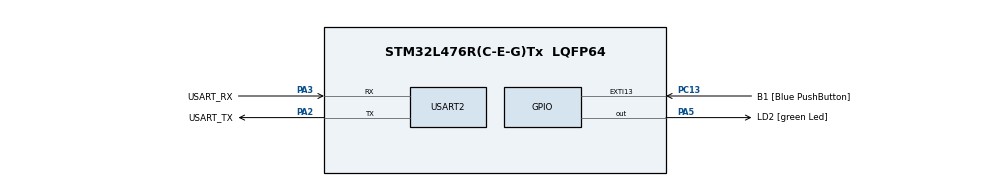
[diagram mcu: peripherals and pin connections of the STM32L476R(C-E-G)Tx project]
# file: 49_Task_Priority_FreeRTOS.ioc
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FREERTOS.Tasks01=defaultTask,0,128,StartDefaultTask,Default,NULL,Dynamic,NULL,NULL
Mcu.Family=STM32L4
Mcu.Name=STM32L476R(C-E-G)Tx
Mcu.Package=LQFP64
NVIC.PriorityGroup=NVIC_PRIORITYGROUP_4
PA13\ (JTMS-SWDIO).GPIO_Label=TMS
PA13\ (JTMS-SWDIO).Mode=Serial_Wire
PA13\ (JTMS-SWDIO).Signal=SYS_JTMS-SWDIO
PA14\ (JTCK-SWCLK).GPIO_Label=TCK
PA14\ (JTCK-SWCLK).Mode=Serial_Wire
PA14\ (JTCK-SWCLK).Signal=SYS_JTCK-SWCLK
PA2.GPIO_Label=USART_TX
PA2.GPIO_Mode=GPIO_MODE_AF_PP
PA2.GPIO_PuPd=GPIO_NOPULL
PA2.GPIO_Speed=GPIO_SPEED_FREQ_VERY_HIGH
PA2.Mode=Asynchronous
PA2.Signal=USART2_TX
PA3.GPIO_Label=USART_RX
PA3.GPIO_Mode=GPIO_MODE_AF_PP
PA3.GPIO_PuPd=GPIO_NOPULL
PA3.GPIO_Speed=GPIO_SPEED_FREQ_VERY_HIGH
PA3.Mode=Asynchronous
PA3.Signal=USART2_RX
PA5.GPIO_Label=LD2 [green Led]
PA5.GPIO_ModeDefaultOutputPP=GPIO_MODE_OUTPUT_PP
PA5.GPIO_PuPd=GPIO_NOPULL
PA5.GPIO_Speed=GPIO_SPEED_FREQ_LOW
PA5.Signal=GPIO_Output
PB3\ (JTDO-TRACESWO).GPIO_Label=SWO
PB3\ (JTDO-TRACESWO).Signal=SYS_JTDO-SWO
PC13.GPIO_Label=B1 [Blue PushButton]
PC13.GPIO_ModeDefaultEXTI=GPIO_MODE_IT_FALLING
PC13.GPIO_PuPd=GPIO_NOPULL
PC13.Signal=GPXTI13
PC14-OSC32_IN\ (PC14).Mode=LSE-External-Oscillator
PC14-OSC32_IN\ (PC14).Signal=RCC_OSC32_IN
PC15-OSC32_OUT\ (PC15).Mode=LSE-External-Oscillator
PC15-OSC32_OUT\ (PC15).Signal=RCC_OSC32_OUT
PH0-OSC_IN\ (PH0).Signal=RCC_OSC_IN
PH1-OSC_OUT\ (PH1).Signal=RCC_OSC_OUT
ProjectManager.HeapSize=0x200
ProjectManager.StackSize=0x400
ProjectManager.TargetToolchain=STM32CubeIDE
RCC.ADCFreq_Value=64000000
RCC.AHBFreq_Value=80000000
RCC.APB1Freq_Value=80000000
RCC.APB1TimFreq_Value=80000000
RCC.APB2Freq_Value=80000000
RCC.APB2TimFreq_Value=80000000
RCC.CortexFreq_Value=80000000
RCC.HCLKFreq_Value=80000000
RCC.HSE_VALUE=8000000
RCC.HSI_VALUE=16000000
RCC.MSI_VALUE=4000000
RCC.PLLN=10
RCC.PLLSourceVirtual=RCC_PLLSOURCE_HSI
RCC.PREFETCH_ENABLE=1
RCC.SYSCLKFreq_VALUE=80000000
RCC.SYSCLKSource=RCC_SYSCLKSOURCE_PLLCLK
RCC.USBFreq_Value=64000000
RCC.VCOOutputFreq_Value=160000000
USART2.VirtualMode-Asynchronous=VM_ASYNC
VP_FREERTOS_VS_CMSIS_V1.Mode=CMSIS_V1
board=NUCLEO-L476RG

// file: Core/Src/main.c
#include "main.h"
#include "FreeRTOS.h"
#include "task.h"
#include <stdio.h>

/* UART Handle */
UART_HandleTypeDef huart2;

/* Function Prototypes */
void SystemClock_Config(void);
static void MX_GPIO_Init(void);
static void MX_USART2_UART_Init(void);

/* Task Functions */
void HighPriorityTask(void *params);
void MediumPriorityTask(void *params);
void LowPriorityTask(void *params);

/* Redirect printf to UART */
int _write(int file, char *ptr, int len)
{
    HAL_UART_Transmit(&huart2,(uint8_t*)ptr,len,HAL_MAX_DELAY);
    return len;
}

int main(void)
{
    HAL_Init();
    SystemClock_Config();
    MX_GPIO_Init();
    MX_USART2_UART_Init();

    /* Create Tasks */

    xTaskCreate(HighPriorityTask,
                "High Priority",
                200,
                NULL,
                3,
                NULL);

    xTaskCreate(MediumPriorityTask,
                "Medium Priority",
                200,
                NULL,
                2,
                NULL);

    xTaskCreate(LowPriorityTask,
                "Low Priority",
                200,
                NULL,
                1,
                NULL);

    vTaskStartScheduler();

    while(1);
}

/* High Priority Task */
void HighPriorityTask(void *params)
{
    while(1)
    {
        HAL_GPIO_TogglePin(GPIOA, GPIO_PIN_5);
        printf("High Priority Task Running\r\n");
        vTaskDelay(pdMS_TO_TICKS(500));
    }
}

/* Medium Priority Task */
void MediumPriorityTask(void *params)
{
    while(1)
    {
        printf("Medium Priority Task Running\r\n");
        vTaskDelay(pdMS_TO_TICKS(1000));
    }
}

/* Low Priority Task */
void LowPriorityTask(void *params)
{
    while(1)
    {
        printf("Low Priority Task Running\r\n");
        vTaskDelay(pdMS_TO_TICKS(2000));
    }
}

/* GPIO Init */
static void MX_GPIO_Init(void)
{
    GPIO_InitTypeDef GPIO_InitStruct = {0};

    __HAL_RCC_GPIOA_CLK_ENABLE();

    GPIO_InitStruct.Pin = GPIO_PIN_5;
    GPIO_InitStruct.Mode = GPIO_MODE_OUTPUT_PP;
    GPIO_InitStruct.Pull = GPIO_NOPULL;
    GPIO_InitStruct.Speed = GPIO_SPEED_FREQ_LOW;

    HAL_GPIO_Init(GPIOA, &GPIO_InitStruct);
}

/* UART Init */
static void MX_USART2_UART_Init(void)
{
    huart2.Instance = USART2;
    huart2.Init.BaudRate = 115200;
    huart2.Init.WordLength = UART_WORDLENGTH_8B;
    huart2.Init.StopBits = UART_STOPBITS_1;
    huart2.Init.Parity = UART_PARITY_NONE;
    huart2.Init.Mode = UART_MODE_TX_RX;
    huart2.Init.HwFlowCtl = UART_HWCONTROL_NONE;
    huart2.Init.OverSampling = UART_OVERSAMPLING_16;

    if (HAL_UART_Init(&huart2) != HAL_OK)
    {
        Error_Handler();
    }
}
void SystemClock_Config(void)
{
  RCC_OscInitTypeDef RCC_OscInitStruct = {0};
  RCC_ClkInitTypeDef RCC_ClkInitStruct = {0};

  HAL_RCC_DeInit();

  RCC_OscInitStruct.OscillatorType = RCC_OSCILLATORTYPE_MSI;
  RCC_OscInitStruct.MSIState = RCC_MSI_ON;
  RCC_OscInitStruct.MSIClockRange = RCC_MSIRANGE_6;
  RCC_OscInitStruct.MSICalibrationValue = RCC_MSICALIBRATION_DEFAULT;
  RCC_OscInitStruct.PLL.PLLState = RCC_PLL_NONE;

  HAL_RCC_OscConfig(&RCC_OscInitStruct);

  RCC_ClkInitStruct.ClockType =
        RCC_CLOCKTYPE_HCLK |
        RCC_CLOCKTYPE_SYSCLK |
        RCC_CLOCKTYPE_PCLK1 |
        RCC_CLOCKTYPE_PCLK2;

  RCC_ClkInitStruct.SYSCLKSource = RCC_SYSCLKSOURCE_MSI;
  RCC_ClkInitStruct.AHBCLKDivider = RCC_SYSCLK_DIV1;
  RCC_ClkInitStruct.APB1CLKDivider = RCC_HCLK_DIV1;
  RCC_ClkInitStruct.APB2CLKDivider = RCC_HCLK_DIV1;

  HAL_RCC_ClockConfig(&RCC_ClkInitStruct, FLASH_LATENCY_0);
}
void Error_Handler(void)
{
  __disable_irq();
  while (1)
  {
  }
}
